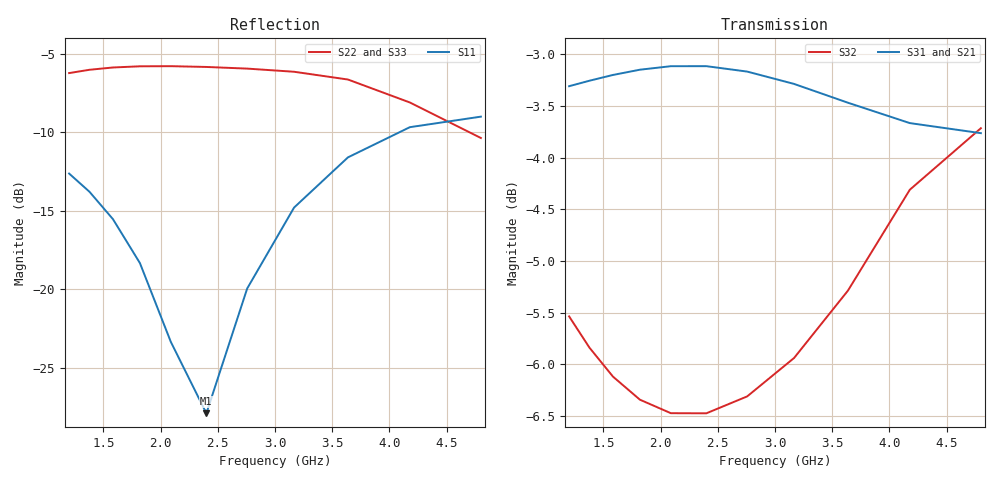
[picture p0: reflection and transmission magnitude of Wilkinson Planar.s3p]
! Generated by circuitRF - EM: Full-wave planar
! circuitRF-EM setup: Wilkinson Planar
! circuitRF-EM layout: Wilkinson/layout/Wilkinson.clay
! circuitRF-EM written: 2026-11-15 21:49:48Z
! circuitRF-EM stamp: 20261115T214948Z-af98dee5
! circuitRF-EM geometry: 81c4eb8c1c774e20
! circuitRF-EM mesh settings: 160092dd3dfb76a4
! circuitRF-EM ports: ce73f9f30e1aafc6
! circuitRF-EM mesh unknowns: 5466
! circuitRF-EM model: grounded-edge-port-2026-10-14
! Port[1] = 1
! Port[2] = 2
! Port[3] = 3
! circuitRF-EM port 1: '1' at (0, 0 mil), edge, de-embedded, 50 Ohm
! circuitRF-EM port 2: '2' at (891.7424, 382.0409 mil), edge, de-embedded, 50 Ohm
! circuitRF-EM port 3: '3' at (891.7424, -382.0409 mil), edge, de-embedded, 50 Ohm
! circuitRF-EM: port N of this file is the label named on the 'port N' line above. A circuit that composes this result binds its nets in that order; two ports of a reciprocal part swapped gives a plausible curve of a different structure.
! Port 1 = P01  1  net=n1  ref=ground  calibrated
! Port 2 = P02  2  net=n3  ref=ground  calibrated
! Port 3 = P03  3  net=n5  ref=ground  calibrated
! DC: none, the lowest row is 1.2 GHz; a circuit's DC solve through this file takes that row as DC
! circuitRF-EM: re-running the EM setup rewrites this file. If circuitRF reports it as stale, the layout's cross-section changed after this file was written.
# GHz S RI R 50
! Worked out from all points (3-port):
!   11 points, 1.2 GHz to 4.8 GHz, reference 50 ohm
!   strongest paths, dB at 1.2 GHz, 1.583 GHz, 2.4 GHz, 3.638 GHz, 4.8 GHz:
!     S31: -3.3, -3.2, -3.1, -3.5, -3.8
!     S21: -3.3, -3.2, -3.1, -3.5, -3.8
!     S32: -5.5, -6.1, -6.5, -5.3, -3.7
!   lowest |S11| = -27.9 dB at 2.4 GHz (marker M1), VSWR 1.08, Z = 50.6 - j4 ohm
!   |S11| at or under -10 dB: start of sweep to 4.084 GHz
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1.2  -0.0346 0.2313  0.0117 -0.6832  0.0117 -0.6832
     0.0117 -0.6832  0.482 -0.0836  -0.5072 -0.1491
     0.0117 -0.6832  -0.5072 -0.1491  0.482 -0.0836
1.583409  0.0577 0.157  -0.3278 -0.6094  -0.3278 -0.6094
          -0.3278 -0.6094  0.3249 -0.3927  -0.4219 0.2578
          -0.3278 -0.6094  -0.4219 0.2578  0.3249 -0.3927
1.81886  0.0788 0.0921  -0.5044 -0.4796  -0.5044 -0.4796
         -0.5044 -0.4796  0.1461 -0.4929  -0.2393 0.4183
         -0.5044 -0.4796  -0.2393 0.4183  0.1461 -0.4929
2.089321  0.0651 0.0191  -0.6453 -0.2678  -0.6453 -0.2678
          -0.6453 -0.2678  -0.081 -0.5082  0.0244 0.474
          -0.6453 -0.2678  0.0244 0.474  -0.081 -0.5082
2.4  0.00745 -0.0395  -0.6984 0.0208  -0.6984 0.0208
     -0.6984 0.0208  -0.3136 -0.4043  0.306 0.3628
     -0.6984 0.0208  0.306 0.3628  -0.3136 -0.4043
2.756876  -0.0871 -0.0502  -0.6042 0.3426  -0.6042 0.3426
          -0.6042 0.3426  -0.4776 -0.1658  0.4795 0.0629
          -0.6042 0.3426  0.4795 0.0629  -0.4776 -0.1658
3.166819  -0.1812 0.0182  -0.3285 0.6011  -0.3285 0.6011
          -0.3285 0.6011  -0.4636 0.1703  0.38 -0.3323
          -0.3285 0.6011  0.38 -0.3323  -0.4636 0.1703
3.63772  -0.2061 0.1639  0.0862 0.6653  0.0862 0.6653
         0.0862 0.6653  -0.1624 0.4374  -0.0772 -0.5386
         0.0862 0.6653  -0.0772 -0.5386  -0.1624 0.4374
4.178643  -0.0937 0.3151  0.4875 0.4387  0.4875 0.4387
          0.4875 0.4387  0.3012 0.2543  -0.5962 -0.1233
          0.4875 0.4387  -0.5962 -0.1233  0.3012 0.2543
4.8  0.1387 0.327  0.6469 -0.0448  0.6469 -0.0448
     0.6469 -0.0448  0.0324 -0.3019  -0.1142 0.642
     0.6469 -0.0448  -0.1142 0.642  0.0324 -0.3019
